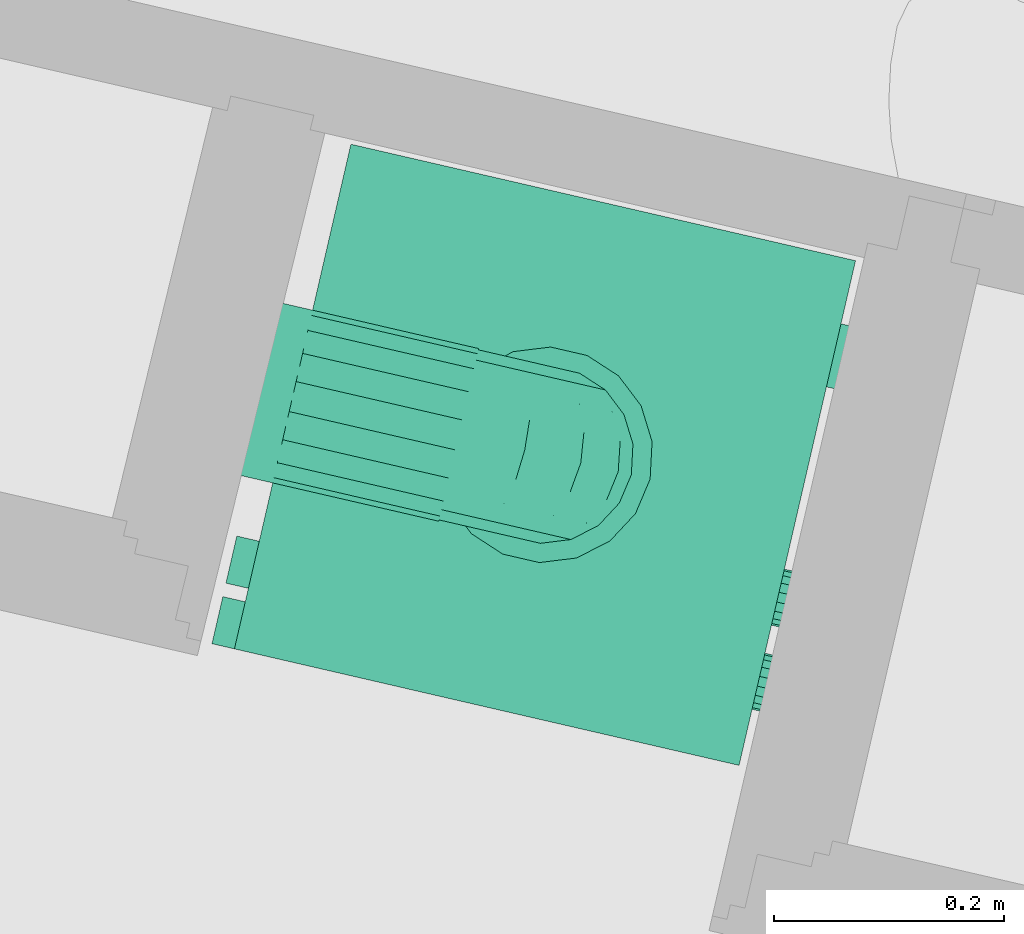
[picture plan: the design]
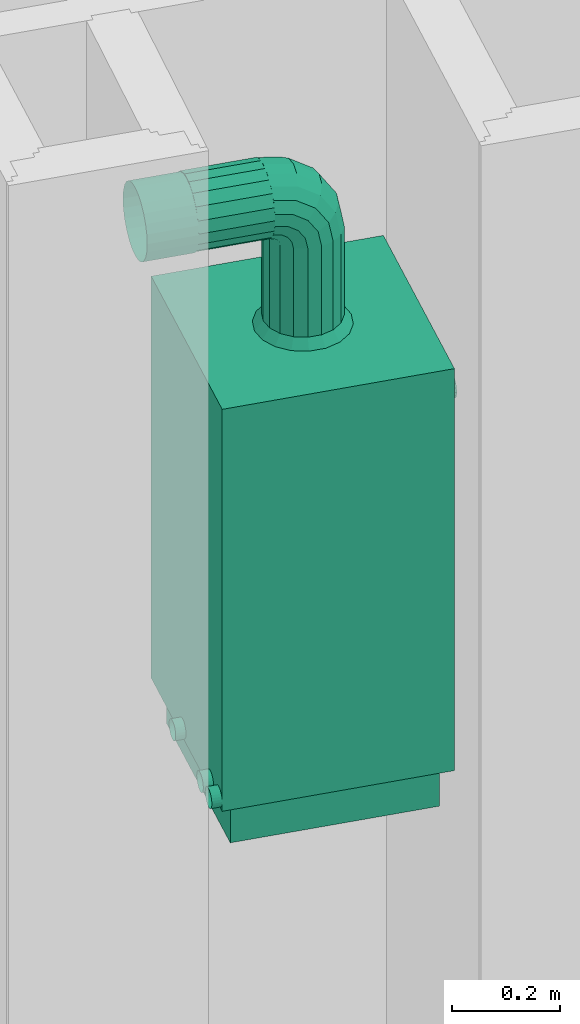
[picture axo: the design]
# One storey, part 74 of 91: 1 energy conversion device.
"""IFC2X3 building model written with IfcOpenShell, lengths in metres."""

from ifc_helpers import new_model, entity, si_unit, converted_unit, derived_unit, money_unit, direction, frame, origin_with_axes, place, context, subcontext, project, spatial, open_shell, faceted_brep, surface_model, source, transform, mapped, type_object, element, save


model = new_model("IFC2X3")

# Units and contexts
model_context = context("Model", 3, precision=1e-05, world=origin_with_axes(), true_north=direction((0.0, 1.0)))
body_context = subcontext(model_context, "Body", "Model", "MODEL_VIEW")
ifc_project = project(units=[si_unit("LENGTHUNIT", "METRE"), si_unit("AREAUNIT", "SQUARE_METRE"), si_unit("VOLUMEUNIT", "CUBIC_METRE"), converted_unit("PLANEANGLEUNIT", "DEGREE", entity("IfcPlaneAngleMeasure", 0.0174532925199), si_unit("PLANEANGLEUNIT", "RADIAN"), dimensions=[0, 0, 0, 0, 0, 0, 0]), si_unit("SOLIDANGLEUNIT", "STERADIAN"), money_unit("EUR"), converted_unit("TIMEUNIT", "Year", entity("IfcTimeMeasure", 31556926.0), si_unit("TIMEUNIT", "SECOND"), dimensions=[0, 0, 1, 0, 0, 0, 0]), si_unit("MASSUNIT", "GRAM", prefix="KILO"), si_unit("THERMODYNAMICTEMPERATUREUNIT", "DEGREE_CELSIUS"), si_unit("LUMINOUSINTENSITYUNIT", "LUMEN"), si_unit("ENERGYUNIT", "JOULE", prefix="MEGA"), derived_unit("THERMALCONDUCTANCEUNIT", [(si_unit("POWERUNIT", "WATT"), 1), (si_unit("LENGTHUNIT", "METRE"), -1), (si_unit("THERMODYNAMICTEMPERATUREUNIT", "KELVIN"), -1)]), derived_unit("SPECIFICHEATCAPACITYUNIT", [(si_unit("ENERGYUNIT", "JOULE"), 1), (si_unit("MASSUNIT", "GRAM", prefix="KILO"), -1), (si_unit("THERMODYNAMICTEMPERATUREUNIT", "KELVIN"), -1)]), derived_unit("MASSDENSITYUNIT", [(si_unit("MASSUNIT", "GRAM", prefix="KILO"), 1), (si_unit("VOLUMEUNIT", "CUBIC_METRE"), -1)])], contexts=[model_context])

# Site, building, storey
site_placement = place(None, origin_with_axes())
site = spatial("IfcSite", under=ifc_project, at=site_placement, CompositionType="ELEMENT")
building_placement = place(site_placement, origin_with_axes())
building = spatial("IfcBuilding", under=site, at=building_placement, CompositionType="ELEMENT")
storey_placement = place(building_placement, frame((0.0, 0.0, 5.44), z_axis=(0.0, 0.0, 1.0), x_axis=(1.0, 0.0, 0.0)))
storey = spatial("IfcBuildingStorey", under=building, at=storey_placement, Name="R+2", CompositionType="ELEMENT", Elevation=5.44)

# Energy conversion device
boiler_type = type_object("IfcBoilerType", PredefinedType="WATER")
shared_shape = source(origin_with_axes(), body_context, "Body", "SurfaceModel", [
    surface_model("IfcShellBasedSurfaceModel", [(-0.2, 0.45, 0.090909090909), (-0.2, 0.47, 0.090909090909), (-0.194564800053, 0.47, 0.0916246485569), (-0.194564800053, 0.45, 0.0916246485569), (-0.205435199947, 0.45, 0.0916246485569), (-0.205435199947, 0.47, 0.0916246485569), (-0.1895, 0.47, 0.0937225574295), (-0.1895, 0.45, 0.0937225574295), (-0.2105, 0.45, 0.0937225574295), (-0.2105, 0.47, 0.0937225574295), (-0.185150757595, 0.47, 0.0970598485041), (-0.185150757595, 0.45, 0.0970598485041), (-0.214849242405, 0.45, 0.0970598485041), (-0.214849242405, 0.47, 0.0970598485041), (-0.181813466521, 0.47, 0.101409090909), (-0.181813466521, 0.45, 0.101409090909), (-0.218186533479, 0.45, 0.101409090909), (-0.218186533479, 0.47, 0.101409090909), (-0.179715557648, 0.47, 0.106473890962), (-0.179715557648, 0.45, 0.106473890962), (-0.220284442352, 0.45, 0.106473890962), (-0.220284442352, 0.47, 0.106473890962), (-0.179, 0.47, 0.111909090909), (-0.179, 0.45, 0.111909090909), (-0.221, 0.45, 0.111909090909), (-0.221, 0.47, 0.111909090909), (-0.179715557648, 0.47, 0.117344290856), (-0.179715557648, 0.45, 0.117344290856), (-0.220284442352, 0.45, 0.117344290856), (-0.220284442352, 0.47, 0.117344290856), (-0.181813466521, 0.47, 0.122409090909), (-0.181813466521, 0.45, 0.122409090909), (-0.218186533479, 0.45, 0.122409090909), (-0.218186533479, 0.47, 0.122409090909), (-0.185150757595, 0.47, 0.126758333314), (-0.185150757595, 0.45, 0.126758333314), (-0.214849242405, 0.45, 0.126758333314), (-0.214849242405, 0.47, 0.126758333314), (-0.1895, 0.47, 0.130095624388), (-0.1895, 0.45, 0.130095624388), (-0.2105, 0.45, 0.130095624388), (-0.2105, 0.47, 0.130095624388), (-0.194564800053, 0.47, 0.132193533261), (-0.194564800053, 0.45, 0.132193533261), (-0.205435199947, 0.45, 0.132193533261), (-0.205435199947, 0.47, 0.132193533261), (-0.2, 0.47, 0.132909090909), (-0.2, 0.45, 0.132909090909)], [open_shell([[[0, 1, 2, 3]], [[4, 5, 1, 0]], [[3, 2, 6, 7]], [[8, 9, 5, 4]], [[7, 6, 10, 11]], [[12, 13, 9, 8]], [[11, 10, 14, 15]], [[16, 17, 13, 12]], [[15, 14, 18, 19]], [[20, 21, 17, 16]], [[19, 18, 22, 23]], [[24, 25, 21, 20]], [[23, 22, 26, 27]], [[28, 29, 25, 24]], [[27, 26, 30, 31]], [[32, 33, 29, 28]], [[31, 30, 34, 35]], [[36, 37, 33, 32]], [[35, 34, 38, 39]], [[40, 41, 37, 36]], [[39, 38, 42, 43]], [[44, 45, 41, 40]], [[43, 42, 46, 47]], [[47, 46, 45, 44]]])]),
    surface_model("IfcShellBasedSurfaceModel", [(-0.375, 0.45, 0.090909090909), (-0.375, 0.47, 0.090909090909), (-0.369564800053, 0.47, 0.0916246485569), (-0.369564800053, 0.45, 0.0916246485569), (-0.380435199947, 0.45, 0.0916246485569), (-0.380435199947, 0.47, 0.0916246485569), (-0.3645, 0.47, 0.0937225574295), (-0.3645, 0.45, 0.0937225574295), (-0.3855, 0.45, 0.0937225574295), (-0.3855, 0.47, 0.0937225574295), (-0.360150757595, 0.47, 0.0970598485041), (-0.360150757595, 0.45, 0.0970598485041), (-0.389849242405, 0.45, 0.0970598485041), (-0.389849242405, 0.47, 0.0970598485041), (-0.356813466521, 0.47, 0.101409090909), (-0.356813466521, 0.45, 0.101409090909), (-0.393186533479, 0.45, 0.101409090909), (-0.393186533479, 0.47, 0.101409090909), (-0.354715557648, 0.47, 0.106473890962), (-0.354715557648, 0.45, 0.106473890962), (-0.395284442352, 0.45, 0.106473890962), (-0.395284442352, 0.47, 0.106473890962), (-0.354, 0.47, 0.111909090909), (-0.354, 0.45, 0.111909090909), (-0.396, 0.45, 0.111909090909), (-0.396, 0.47, 0.111909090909), (-0.354715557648, 0.47, 0.117344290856), (-0.354715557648, 0.45, 0.117344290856), (-0.395284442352, 0.45, 0.117344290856), (-0.395284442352, 0.47, 0.117344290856), (-0.356813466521, 0.47, 0.122409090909), (-0.356813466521, 0.45, 0.122409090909), (-0.393186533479, 0.45, 0.122409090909), (-0.393186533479, 0.47, 0.122409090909), (-0.360150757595, 0.47, 0.126758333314), (-0.360150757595, 0.45, 0.126758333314), (-0.389849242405, 0.45, 0.126758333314), (-0.389849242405, 0.47, 0.126758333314), (-0.3645, 0.47, 0.130095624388), (-0.3645, 0.45, 0.130095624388), (-0.3855, 0.45, 0.130095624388), (-0.3855, 0.47, 0.130095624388), (-0.369564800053, 0.47, 0.132193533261), (-0.369564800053, 0.45, 0.132193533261), (-0.380435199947, 0.45, 0.132193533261), (-0.380435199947, 0.47, 0.132193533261), (-0.375, 0.47, 0.132909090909), (-0.375, 0.45, 0.132909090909)], [open_shell([[[0, 1, 2, 3]], [[4, 5, 1, 0]], [[3, 2, 6, 7]], [[8, 9, 5, 4]], [[7, 6, 10, 11]], [[12, 13, 9, 8]], [[11, 10, 14, 15]], [[16, 17, 13, 12]], [[15, 14, 18, 19]], [[20, 21, 17, 16]], [[19, 18, 22, 23]], [[24, 25, 21, 20]], [[23, 22, 26, 27]], [[28, 29, 25, 24]], [[27, 26, 30, 31]], [[32, 33, 29, 28]], [[31, 30, 34, 35]], [[36, 37, 33, 32]], [[35, 34, 38, 39]], [[40, 41, 37, 36]], [[39, 38, 42, 43]], [[44, 45, 41, 40]], [[43, 42, 46, 47]], [[47, 46, 45, 44]]])]),
    surface_model("IfcShellBasedSurfaceModel", [(-0.429, 0.45, 0.090909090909), (-0.429, 0.47, 0.090909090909), (-0.423564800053, 0.47, 0.0916246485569), (-0.423564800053, 0.45, 0.0916246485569), (-0.434435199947, 0.45, 0.0916246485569), (-0.434435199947, 0.47, 0.0916246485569), (-0.4185, 0.47, 0.0937225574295), (-0.4185, 0.45, 0.0937225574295), (-0.4395, 0.45, 0.0937225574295), (-0.4395, 0.47, 0.0937225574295), (-0.414150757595, 0.47, 0.0970598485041), (-0.414150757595, 0.45, 0.0970598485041), (-0.443849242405, 0.45, 0.0970598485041), (-0.443849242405, 0.47, 0.0970598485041), (-0.410813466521, 0.47, 0.101409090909), (-0.410813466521, 0.45, 0.101409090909), (-0.447186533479, 0.45, 0.101409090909), (-0.447186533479, 0.47, 0.101409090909), (-0.408715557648, 0.47, 0.106473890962), (-0.408715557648, 0.45, 0.106473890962), (-0.449284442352, 0.45, 0.106473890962), (-0.449284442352, 0.47, 0.106473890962), (-0.408, 0.47, 0.111909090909), (-0.408, 0.45, 0.111909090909), (-0.45, 0.45, 0.111909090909), (-0.45, 0.47, 0.111909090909), (-0.408715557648, 0.47, 0.117344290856), (-0.408715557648, 0.45, 0.117344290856), (-0.449284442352, 0.45, 0.117344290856), (-0.449284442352, 0.47, 0.117344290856), (-0.410813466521, 0.47, 0.122409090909), (-0.410813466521, 0.45, 0.122409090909), (-0.447186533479, 0.45, 0.122409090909), (-0.447186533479, 0.47, 0.122409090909), (-0.414150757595, 0.47, 0.126758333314), (-0.414150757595, 0.45, 0.126758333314), (-0.443849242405, 0.45, 0.126758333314), (-0.443849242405, 0.47, 0.126758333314), (-0.4185, 0.47, 0.130095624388), (-0.4185, 0.45, 0.130095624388), (-0.4395, 0.45, 0.130095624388), (-0.4395, 0.47, 0.130095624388), (-0.423564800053, 0.47, 0.132193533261), (-0.423564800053, 0.45, 0.132193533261), (-0.434435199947, 0.45, 0.132193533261), (-0.434435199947, 0.47, 0.132193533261), (-0.429, 0.47, 0.132909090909), (-0.429, 0.45, 0.132909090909)], [open_shell([[[0, 1, 2, 3]], [[4, 5, 1, 0]], [[3, 2, 6, 7]], [[8, 9, 5, 4]], [[7, 6, 10, 11]], [[12, 13, 9, 8]], [[11, 10, 14, 15]], [[16, 17, 13, 12]], [[15, 14, 18, 19]], [[20, 21, 17, 16]], [[19, 18, 22, 23]], [[24, 25, 21, 20]], [[23, 22, 26, 27]], [[28, 29, 25, 24]], [[27, 26, 30, 31]], [[32, 33, 29, 28]], [[31, 30, 34, 35]], [[36, 37, 33, 32]], [[35, 34, 38, 39]], [[40, 41, 37, 36]], [[39, 38, 42, 43]], [[44, 45, 41, 40]], [[43, 42, 46, 47]], [[47, 46, 45, 44]]])]),
    surface_model("IfcShellBasedSurfaceModel", [(-0.225, 0.45, 1.218), (-0.225, 0.55, 1.218), (-0.205070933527, 0.55, 1.22062371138), (-0.205070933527, 0.45, 1.22062371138), (-0.244929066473, 0.45, 1.22062371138), (-0.244929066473, 0.55, 1.22062371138), (-0.1865, 0.55, 1.22831604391), (-0.1865, 0.45, 1.22831604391), (-0.2635, 0.45, 1.22831604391), (-0.2635, 0.55, 1.22831604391), (-0.170552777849, 0.55, 1.24055277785), (-0.170552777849, 0.45, 1.24055277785), (-0.279447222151, 0.45, 1.24055277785), (-0.279447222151, 0.55, 1.24055277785), (-0.158316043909, 0.55, 1.2565), (-0.158316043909, 0.45, 1.2565), (-0.291683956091, 0.45, 1.2565), (-0.291683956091, 0.55, 1.2565), (-0.150623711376, 0.55, 1.27507093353), (-0.150623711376, 0.45, 1.27507093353), (-0.299376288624, 0.45, 1.27507093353), (-0.299376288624, 0.55, 1.27507093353), (-0.148, 0.55, 1.295), (-0.148, 0.45, 1.295), (-0.302, 0.45, 1.295), (-0.302, 0.55, 1.295), (-0.150623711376, 0.55, 1.31492906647), (-0.150623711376, 0.45, 1.31492906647), (-0.299376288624, 0.45, 1.31492906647), (-0.299376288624, 0.55, 1.31492906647), (-0.158316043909, 0.55, 1.3335), (-0.158316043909, 0.45, 1.3335), (-0.291683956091, 0.45, 1.3335), (-0.291683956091, 0.55, 1.3335), (-0.170552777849, 0.55, 1.34944722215), (-0.170552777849, 0.45, 1.34944722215), (-0.279447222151, 0.45, 1.34944722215), (-0.279447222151, 0.55, 1.34944722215), (-0.1865, 0.55, 1.36168395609), (-0.1865, 0.45, 1.36168395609), (-0.2635, 0.45, 1.36168395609), (-0.2635, 0.55, 1.36168395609), (-0.205070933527, 0.55, 1.36937628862), (-0.205070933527, 0.45, 1.36937628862), (-0.244929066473, 0.45, 1.36937628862), (-0.244929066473, 0.55, 1.36937628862), (-0.225, 0.55, 1.372), (-0.225, 0.45, 1.372)], [open_shell([[[0, 1, 2, 3]], [[4, 5, 1, 0]], [[3, 2, 6, 7]], [[8, 9, 5, 4]], [[7, 6, 10, 11]], [[12, 13, 9, 8]], [[11, 10, 14, 15]], [[16, 17, 13, 12]], [[15, 14, 18, 19]], [[20, 21, 17, 16]], [[19, 18, 22, 23]], [[24, 25, 21, 20]], [[23, 22, 26, 27]], [[28, 29, 25, 24]], [[27, 26, 30, 31]], [[32, 33, 29, 28]], [[31, 30, 34, 35]], [[36, 37, 33, 32]], [[35, 34, 38, 39]], [[40, 41, 37, 36]], [[39, 38, 42, 43]], [[44, 45, 41, 40]], [[43, 42, 46, 47]], [[47, 46, 45, 44]]])]),
    faceted_brep([(-0.4275, 0.0225, 0.0), (-0.4275, 0.4275, 0.0), (-0.0225, 0.4275, 0.0), (-0.0225, 0.0225, 0.0), (-0.4275, 0.0225, 0.0909090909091), (-0.4275, 0.4275, 0.0909090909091), (-0.0225, 0.4275, 0.0909090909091), (-0.0225, 0.0225, 0.0909090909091)], [[[0, 1, 2, 3]], [[0, 4, 5, 1]], [[1, 5, 6, 2]], [[2, 6, 7, 3]], [[3, 7, 4, 0]], [[7, 6, 5, 4]]]),
    faceted_brep([(0.0, 0.45, 0.0909090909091), (-0.45, 0.45, 0.0909090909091), (-0.45, 0.45, 1.0), (0.0, 0.45, 1.0), (0.0, 0.0, 0.0909090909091), (-0.45, 0.0, 0.0909090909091), (-0.45, 0.0, 0.818181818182), (-0.45, 0.0225, 0.818181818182), (-0.45, 0.0225, 1.0), (0.0, 0.0225, 1.0), (0.0, 0.0225, 0.818181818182), (0.0, 0.0, 0.818181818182)], [[[0, 1, 2, 3]], [[4, 5, 1, 0]], [[1, 5, 6, 7, 8, 2]], [[3, 2, 8, 9]], [[0, 3, 9, 10, 11, 4]], [[11, 6, 5, 4]], [[10, 7, 6, 11]], [[9, 8, 7, 10]]]),
    faceted_brep([(-0.45, 0.0, 0.818181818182), (-0.45, 0.0225, 0.818181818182), (0.0, 0.0225, 0.818181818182), (0.0, 0.0, 0.818181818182), (-0.45, 0.0, 1.0), (-0.45, 0.0225, 1.0), (0.0, 0.0225, 1.0), (0.0, 0.0, 1.0)], [[[0, 1, 2, 3]], [[0, 4, 5, 1]], [[1, 5, 6, 2]], [[2, 6, 7, 3]], [[3, 7, 4, 0]], [[7, 6, 5, 4]]]),
    faceted_brep([(-0.32349231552, 0.0, 0.900540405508), (-0.325, 0.0, 0.909090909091), (-0.32349231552, 0.0, 0.917641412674), (-0.319151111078, 0.0, 0.925160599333), (-0.3125, 0.0, 0.930741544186), (-0.304341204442, 0.0, 0.933711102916), (-0.295658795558, 0.0, 0.933711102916), (-0.2875, 0.0, 0.930741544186), (-0.280848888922, 0.0, 0.925160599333), (-0.27650768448, 0.0, 0.917641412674), (-0.275, 0.0, 0.909090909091), (-0.27650768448, 0.0, 0.900540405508), (-0.280848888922, 0.0, 0.893021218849), (-0.2875, 0.0, 0.887440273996), (-0.295658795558, 0.0, 0.884470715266), (-0.304341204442, 0.0, 0.884470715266), (-0.3125, 0.0, 0.887440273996), (-0.319151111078, 0.0, 0.893021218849), (-0.32349231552, -0.02, 0.900540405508), (-0.325, -0.02, 0.909090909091), (-0.32349231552, -0.02, 0.917641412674), (-0.319151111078, -0.02, 0.925160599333), (-0.3125, -0.02, 0.930741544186), (-0.304341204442, -0.02, 0.933711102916), (-0.295658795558, -0.02, 0.933711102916), (-0.2875, -0.02, 0.930741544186), (-0.280848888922, -0.02, 0.925160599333), (-0.27650768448, -0.02, 0.917641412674), (-0.275, -0.02, 0.909090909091), (-0.27650768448, -0.02, 0.900540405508), (-0.280848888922, -0.02, 0.893021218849), (-0.2875, -0.02, 0.887440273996), (-0.295658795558, -0.02, 0.884470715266), (-0.304341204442, -0.02, 0.884470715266), (-0.3125, -0.02, 0.887440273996), (-0.319151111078, -0.02, 0.893021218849)], [[[0, 1, 2, 3, 4, 5, 6, 7, 8, 9, 10, 11, 12, 13, 14, 15, 16, 17]], [[0, 18, 19, 1]], [[1, 19, 20, 2]], [[2, 20, 21, 3]], [[3, 21, 22, 4]], [[4, 22, 23, 5]], [[5, 23, 24, 6]], [[6, 24, 25, 7]], [[7, 25, 26, 8]], [[8, 26, 27, 9]], [[9, 27, 28, 10]], [[10, 28, 29, 11]], [[11, 29, 30, 12]], [[12, 30, 31, 13]], [[13, 31, 32, 14]], [[14, 32, 33, 15]], [[15, 33, 34, 16]], [[16, 34, 35, 17]], [[17, 35, 18, 0]], [[18, 35, 34, 33, 32, 31, 30, 29, 28, 27, 26, 25, 24, 23, 22, 21, 20, 19]]]),
    faceted_brep([(-0.39849231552, 0.0, 0.900540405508), (-0.4, 0.0, 0.909090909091), (-0.39849231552, 0.0, 0.917641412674), (-0.394151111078, 0.0, 0.925160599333), (-0.3875, 0.0, 0.930741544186), (-0.379341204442, 0.0, 0.933711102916), (-0.370658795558, 0.0, 0.933711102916), (-0.3625, 0.0, 0.930741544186), (-0.355848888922, 0.0, 0.925160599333), (-0.35150768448, 0.0, 0.917641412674), (-0.35, 0.0, 0.909090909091), (-0.35150768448, 0.0, 0.900540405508), (-0.355848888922, 0.0, 0.893021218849), (-0.3625, 0.0, 0.887440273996), (-0.370658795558, 0.0, 0.884470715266), (-0.379341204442, 0.0, 0.884470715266), (-0.3875, 0.0, 0.887440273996), (-0.394151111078, 0.0, 0.893021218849), (-0.39849231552, -0.02, 0.900540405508), (-0.4, -0.02, 0.909090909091), (-0.39849231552, -0.02, 0.917641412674), (-0.394151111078, -0.02, 0.925160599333), (-0.3875, -0.02, 0.930741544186), (-0.379341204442, -0.02, 0.933711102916), (-0.370658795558, -0.02, 0.933711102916), (-0.3625, -0.02, 0.930741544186), (-0.355848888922, -0.02, 0.925160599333), (-0.35150768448, -0.02, 0.917641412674), (-0.35, -0.02, 0.909090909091), (-0.35150768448, -0.02, 0.900540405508), (-0.355848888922, -0.02, 0.893021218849), (-0.3625, -0.02, 0.887440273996), (-0.370658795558, -0.02, 0.884470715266), (-0.379341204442, -0.02, 0.884470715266), (-0.3875, -0.02, 0.887440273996), (-0.394151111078, -0.02, 0.893021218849)], [[[0, 1, 2, 3, 4, 5, 6, 7, 8, 9, 10, 11, 12, 13, 14, 15, 16, 17]], [[0, 18, 19, 1]], [[1, 19, 20, 2]], [[2, 20, 21, 3]], [[3, 21, 22, 4]], [[4, 22, 23, 5]], [[5, 23, 24, 6]], [[6, 24, 25, 7]], [[7, 25, 26, 8]], [[8, 26, 27, 9]], [[9, 27, 28, 10]], [[10, 28, 29, 11]], [[11, 29, 30, 12]], [[12, 30, 31, 13]], [[13, 31, 32, 14]], [[14, 32, 33, 15]], [[15, 33, 34, 16]], [[16, 34, 35, 17]], [[17, 35, 18, 0]], [[18, 35, 34, 33, 32, 31, 30, 29, 28, 27, 26, 25, 24, 23, 22, 21, 20, 19]]]),
    faceted_brep([(-0.1125, 0.0, 0.878787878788), (-0.1125, 0.0, 0.939393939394), (-0.05625, 0.0, 0.939393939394), (-0.05625, 0.0, 0.878787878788), (-0.1125, -0.02, 0.878787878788), (-0.1125, -0.02, 0.939393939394), (-0.05625, -0.02, 0.939393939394), (-0.05625, -0.02, 0.878787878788)], [[[0, 1, 2, 3]], [[0, 4, 5, 1]], [[1, 5, 6, 2]], [[2, 6, 7, 3]], [[3, 7, 4, 0]], [[7, 6, 5, 4]]]),
    surface_model("IfcShellBasedSurfaceModel", [(-0.198664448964, 0.297356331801, 1.22), (-0.198664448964, 0.297356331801, 1.02), (-0.225, 0.302, 1.02), (-0.225, 0.302, 1.22), (-0.175505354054, 0.28398542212, 1.22), (-0.175505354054, 0.28398542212, 1.02), (-0.192935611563, 0.313096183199, 1.0), (-0.225, 0.31875, 1.0), (-0.251335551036, 0.297356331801, 1.02), (-0.251335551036, 0.297356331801, 1.22), (-0.158316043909, 0.2635, 1.22), (-0.158316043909, 0.2635, 1.02), (-0.164738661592, 0.296816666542, 1.0), (-0.257064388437, 0.313096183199, 1.0), (-0.274494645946, 0.28398542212, 1.02), (-0.274494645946, 0.28398542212, 1.22), (-0.149169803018, 0.23837090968, 1.22), (-0.149169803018, 0.23837090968, 1.02), (-0.143810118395, 0.271875, 1.0), (-0.285261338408, 0.296816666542, 1.0), (-0.291683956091, 0.2635, 1.02), (-0.291683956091, 0.2635, 1.22), (-0.149169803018, 0.21162909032, 1.22), (-0.149169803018, 0.21162909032, 1.02), (-0.132674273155, 0.241279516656, 1.0), (-0.306189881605, 0.271875, 1.0), (-0.300830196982, 0.23837090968, 1.02), (-0.300830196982, 0.23837090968, 1.22), (-0.158316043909, 0.1865, 1.22), (-0.158316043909, 0.1865, 1.02), (-0.132674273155, 0.208720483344, 1.0), (-0.317325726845, 0.241279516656, 1.0), (-0.300830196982, 0.21162909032, 1.02), (-0.300830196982, 0.21162909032, 1.22), (-0.175505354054, 0.16601457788, 1.22), (-0.175505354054, 0.16601457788, 1.02), (-0.143810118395, 0.178125, 1.0), (-0.317325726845, 0.208720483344, 1.0), (-0.291683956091, 0.1865, 1.02), (-0.291683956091, 0.1865, 1.22), (-0.198664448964, 0.152643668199, 1.22), (-0.198664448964, 0.152643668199, 1.02), (-0.164738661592, 0.153183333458, 1.0), (-0.306189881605, 0.178125, 1.0), (-0.274494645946, 0.16601457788, 1.02), (-0.274494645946, 0.16601457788, 1.22), (-0.225, 0.148, 1.22), (-0.225, 0.148, 1.02), (-0.192935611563, 0.136903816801, 1.0), (-0.285261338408, 0.153183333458, 1.0), (-0.251335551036, 0.152643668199, 1.02), (-0.251335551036, 0.152643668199, 1.22), (-0.225, 0.13125, 1.0), (-0.257064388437, 0.136903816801, 1.0)], [open_shell([[[0, 1, 2, 3]], [[4, 5, 1, 0]], [[1, 6, 7, 2]], [[3, 2, 8, 9]], [[10, 11, 5, 4]], [[5, 12, 6, 1]], [[2, 7, 13, 8]], [[9, 8, 14, 15]], [[16, 17, 11, 10]], [[11, 18, 12, 5]], [[8, 13, 19, 14]], [[15, 14, 20, 21]], [[22, 23, 17, 16]], [[17, 24, 18, 11]], [[14, 19, 25, 20]], [[21, 20, 26, 27]], [[28, 29, 23, 22]], [[23, 30, 24, 17]], [[20, 25, 31, 26]], [[27, 26, 32, 33]], [[34, 35, 29, 28]], [[29, 36, 30, 23]], [[26, 31, 37, 32]], [[33, 32, 38, 39]], [[40, 41, 35, 34]], [[35, 42, 36, 29]], [[32, 37, 43, 38]], [[39, 38, 44, 45]], [[46, 47, 41, 40]], [[41, 48, 42, 35]], [[38, 43, 49, 44]], [[45, 44, 50, 51]], [[51, 50, 47, 46]], [[47, 52, 48, 41]], [[44, 49, 53, 50]], [[50, 53, 52, 47]]])]),
    faceted_brep([(-0.300830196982, 0.218508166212, 1.2545834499), (-0.300830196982, 0.21162909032, 1.22), (-0.291683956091, 0.1865, 1.22), (-0.291683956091, 0.195291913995, 1.26419993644), (-0.300830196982, 0.243214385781, 1.24434979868), (-0.300830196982, 0.23837090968, 1.22), (-0.291683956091, 0.2635, 1.22), (-0.274494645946, 0.28398542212, 1.22), (-0.251335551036, 0.297356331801, 1.22), (-0.225, 0.302, 1.22), (-0.198664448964, 0.297356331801, 1.22), (-0.175505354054, 0.28398542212, 1.22), (-0.158316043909, 0.2635, 1.22), (-0.149169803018, 0.23837090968, 1.22), (-0.149169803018, 0.21162909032, 1.22), (-0.158316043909, 0.1865, 1.22), (-0.175505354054, 0.16601457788, 1.22), (-0.198664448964, 0.152643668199, 1.22), (-0.225, 0.148, 1.22), (-0.251335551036, 0.152643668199, 1.22), (-0.274494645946, 0.16601457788, 1.22), (-0.274494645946, 0.176365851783, 1.27203936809), (-0.300830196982, 0.238098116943, 1.28390188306), (-0.291683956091, 0.220329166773, 1.30167083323), (-0.300830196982, 0.257007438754, 1.26499256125), (-0.291683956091, 0.266430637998, 1.23473331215), (-0.274494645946, 0.28535670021, 1.2268938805), (-0.251335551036, 0.297709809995, 1.22177705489), (-0.198664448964, 0.297709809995, 1.22177705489), (-0.175505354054, 0.28535670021, 1.2268938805), (-0.158316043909, 0.266430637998, 1.23473331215), (-0.149169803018, 0.243214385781, 1.24434979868), (-0.149169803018, 0.218508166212, 1.2545834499), (-0.158316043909, 0.195291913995, 1.26419993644), (-0.175505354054, 0.176365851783, 1.27203936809), (-0.198664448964, 0.164012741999, 1.2771561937), (-0.225, 0.159722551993, 1.27893324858), (-0.251335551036, 0.164012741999, 1.2771561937), (-0.274494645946, 0.205843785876, 1.31615621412), (-0.291683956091, 0.257800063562, 1.32670808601), (-0.300830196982, 0.267416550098, 1.30349183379), (-0.300830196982, 0.277650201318, 1.27878561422), (-0.291683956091, 0.274776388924, 1.24722361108), (-0.274494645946, 0.289261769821, 1.23273823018), (-0.251335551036, 0.298716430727, 1.22328356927), (-0.198664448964, 0.298716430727, 1.22328356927), (-0.175505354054, 0.289261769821, 1.23273823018), (-0.158316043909, 0.274776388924, 1.24722361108), (-0.149169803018, 0.257007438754, 1.26499256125), (-0.149169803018, 0.238098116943, 1.28390188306), (-0.158316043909, 0.220329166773, 1.30167083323), (-0.175505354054, 0.205843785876, 1.31615621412), (-0.198664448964, 0.196389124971, 1.32561087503), (-0.225, 0.193105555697, 1.3288944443), (-0.251335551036, 0.196389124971, 1.32561087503), (-0.274494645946, 0.249960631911, 1.34563414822), (-0.291683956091, 0.302, 1.3355), (-0.300830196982, 0.302, 1.31037090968), (-0.300830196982, 0.302, 1.28362909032), (-0.291683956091, 0.287266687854, 1.255569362), (-0.274494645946, 0.295106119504, 1.23664329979), (-0.251335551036, 0.300222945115, 1.22429019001), (-0.198664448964, 0.300222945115, 1.22429019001), (-0.175505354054, 0.295106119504, 1.23664329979), (-0.158316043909, 0.287266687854, 1.255569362), (-0.149169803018, 0.277650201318, 1.27878561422), (-0.149169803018, 0.267416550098, 1.30349183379), (-0.158316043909, 0.257800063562, 1.32670808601), (-0.175505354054, 0.249960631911, 1.34563414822), (-0.198664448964, 0.244843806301, 1.357987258), (-0.225, 0.243066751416, 1.36227744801), (-0.251335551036, 0.244843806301, 1.357987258), (-0.274494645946, 0.302, 1.35598542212), (-0.291683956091, 0.302, 1.2585), (-0.251335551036, 0.302, 1.3693563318), (-0.225, 0.302, 1.374), (-0.198664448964, 0.302, 1.3693563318), (-0.175505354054, 0.302, 1.35598542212), (-0.158316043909, 0.302, 1.3355), (-0.149169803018, 0.302, 1.31037090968), (-0.149169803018, 0.302, 1.28362909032), (-0.158316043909, 0.302, 1.2585), (-0.175505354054, 0.302, 1.23801457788), (-0.198664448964, 0.302, 1.2246436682), (-0.251335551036, 0.302, 1.2246436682), (-0.274494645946, 0.302, 1.23801457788)], [[[0, 1, 2, 3]], [[1, 0, 4, 5]], [[2, 1, 5, 6, 7, 8, 9, 10, 11, 12, 13, 14, 15, 16, 17, 18, 19, 20]], [[3, 2, 20, 21]], [[22, 0, 3, 23]], [[0, 22, 24, 4]], [[6, 5, 4, 25]], [[26, 7, 6, 25]], [[7, 26, 27, 8]], [[8, 27, 9]], [[28, 10, 9]], [[10, 28, 29, 11]], [[30, 12, 11, 29]], [[12, 30, 31, 13]], [[32, 14, 13, 31]], [[15, 14, 32, 33]], [[34, 16, 15, 33]], [[17, 16, 34, 35]], [[36, 18, 17, 35]], [[19, 18, 36, 37]], [[21, 20, 19, 37]], [[23, 3, 21, 38]], [[22, 23, 39, 40]], [[24, 22, 40, 41]], [[4, 24, 42, 25]], [[43, 26, 25, 42]], [[26, 43, 44, 27]], [[27, 44, 9]], [[45, 28, 9]], [[28, 45, 46, 29]], [[29, 46, 47, 30]], [[31, 30, 47, 48]], [[49, 32, 31, 48]], [[32, 49, 50, 33]], [[51, 34, 33, 50]], [[35, 34, 51, 52]], [[53, 36, 35, 52]], [[54, 37, 36, 53]], [[38, 21, 37, 54]], [[39, 23, 38, 55]], [[40, 39, 56, 57]], [[41, 40, 57, 58]], [[59, 42, 24, 41]], [[42, 59, 60, 43]], [[43, 60, 61, 44]], [[44, 61, 9]], [[62, 45, 9]], [[45, 62, 63, 46]], [[46, 63, 64, 47]], [[47, 64, 65, 48]], [[66, 49, 48, 65]], [[50, 49, 66, 67]], [[68, 51, 50, 67]], [[52, 51, 68, 69]], [[53, 52, 69, 70]], [[71, 54, 53, 70]], [[55, 38, 54, 71]], [[56, 39, 55, 72]], [[73, 58, 57, 56, 72, 74, 75, 76, 77, 78, 79, 80, 81, 82, 83, 9, 84, 85]], [[59, 41, 58, 73]], [[59, 73, 85, 60]], [[60, 85, 84, 61]], [[61, 84, 9]], [[62, 9, 83]], [[63, 62, 83, 82]], [[63, 82, 81, 64]], [[65, 64, 81, 80]], [[66, 65, 80, 79]], [[67, 66, 79, 78]], [[77, 68, 67, 78]], [[69, 68, 77, 76]], [[75, 70, 69, 76]], [[71, 70, 75, 74]], [[72, 55, 71, 74]]]),
    surface_model("IfcShellBasedSurfaceModel", [(-0.152643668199, 0.45, 1.32333555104), (-0.152643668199, 0.302, 1.32333555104), (-0.148, 0.302, 1.297), (-0.148, 0.45, 1.297), (-0.16601457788, 0.45, 1.34649464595), (-0.16601457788, 0.302, 1.34649464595), (-0.152643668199, 0.302, 1.27066444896), (-0.152643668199, 0.45, 1.27066444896), (-0.1865, 0.45, 1.36368395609), (-0.1865, 0.302, 1.36368395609), (-0.16601457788, 0.302, 1.24750535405), (-0.16601457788, 0.45, 1.24750535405), (-0.21162909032, 0.45, 1.37283019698), (-0.21162909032, 0.302, 1.37283019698), (-0.1865, 0.302, 1.23031604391), (-0.1865, 0.45, 1.23031604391), (-0.23837090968, 0.45, 1.37283019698), (-0.23837090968, 0.302, 1.37283019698), (-0.21162909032, 0.302, 1.22116980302), (-0.21162909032, 0.45, 1.22116980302), (-0.2635, 0.45, 1.36368395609), (-0.2635, 0.302, 1.36368395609), (-0.23837090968, 0.302, 1.22116980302), (-0.23837090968, 0.45, 1.22116980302), (-0.28398542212, 0.45, 1.34649464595), (-0.28398542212, 0.302, 1.34649464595), (-0.2635, 0.302, 1.23031604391), (-0.2635, 0.45, 1.23031604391), (-0.297356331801, 0.45, 1.32333555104), (-0.297356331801, 0.302, 1.32333555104), (-0.28398542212, 0.302, 1.24750535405), (-0.28398542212, 0.45, 1.24750535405), (-0.302, 0.45, 1.297), (-0.302, 0.302, 1.297), (-0.297356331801, 0.302, 1.27066444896), (-0.297356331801, 0.45, 1.27066444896)], [open_shell([[[0, 1, 2, 3]], [[4, 5, 1, 0]], [[3, 2, 6, 7]], [[8, 9, 5, 4]], [[7, 6, 10, 11]], [[12, 13, 9, 8]], [[11, 10, 14, 15]], [[16, 17, 13, 12]], [[15, 14, 18, 19]], [[20, 21, 17, 16]], [[19, 18, 22, 23]], [[24, 25, 21, 20]], [[23, 22, 26, 27]], [[28, 29, 25, 24]], [[27, 26, 30, 31]], [[32, 33, 29, 28]], [[31, 30, 34, 35]], [[35, 34, 33, 32]]])]),
])
energy_conversion_device_placement = place(storey_placement, frame((-12.2661064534, -3.1479817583, 0.9), z_axis=(0.0, 0.0, 1.0), x_axis=(0.224876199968, 0.974387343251, 0.0)))
element("IfcEnergyConversionDevice", 1, at=energy_conversion_device_placement, inside=storey, type_object=boiler_type, Name="002", context=body_context, shape_type="MappedRepresentation", body=[
    mapped(shared_shape, transform((0.0, 0.0, 0.0))),
])

save(model, "model.ifc")
